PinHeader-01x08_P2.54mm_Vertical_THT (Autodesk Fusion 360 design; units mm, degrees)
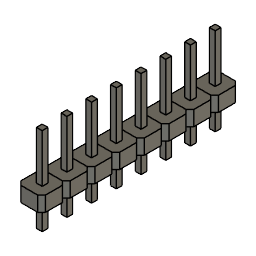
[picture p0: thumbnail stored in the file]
description: Part Number
part number: top_pcb 1.8.1
part number: top_pcb 1.8.2
part number: PinHeader-01x08_P2.54mm_Vertical_THT
base_feature "Base Feature1"
base_feature "Base Feature1"
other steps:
create_component "CreateComponent1"
create_component "CreateComponent2"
